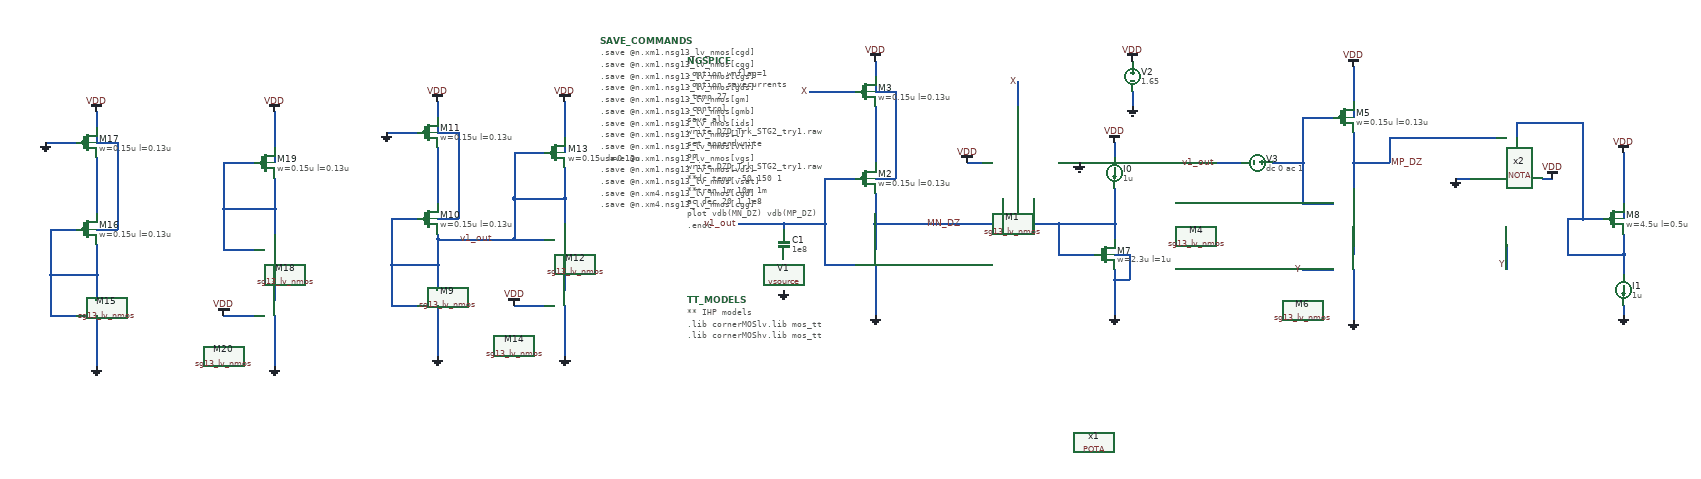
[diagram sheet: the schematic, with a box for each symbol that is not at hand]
v {xschem version=3.4.6 file_version=1.2}
G {}
K {}
V {}
S {}
E {}
N 370 -200 370 -100 {lab=GND}
N 270 -200 330 -200 {lab=v1_out}
N 270 -280 270 -200 {lab=v1_out}
N 270 -370 330 -370 {lab=v1_out}
N 370 -510 370 -400 {lab=#net1}
N 370 -370 410 -370 {lab=VDD}
N 410 -540 410 -370 {lab=VDD}
N 370 -600 370 -540 {lab=VDD}
N 370 -540 410 -540 {lab=VDD}
N 270 -370 270 -280 {lab=v1_out}
N 875 -540 875 -510 {lab=GND}
N 370 -280 370 -230 {lab=MN_DZ}
N 1310 -320 1310 -220 {lab=#net2}
N 1210 -320 1270 -320 {lab=#net3}
N 1210 -400 1210 -320 {lab=#net3}
N 1210 -490 1270 -490 {lab=#net3}
N 1150 -400 1210 -400 {lab=#net3}
N 1210 -490 1210 -400 {lab=#net3}
N 1310 -400 1310 -350 {lab=MP_DZ}
N 1310 -590 1310 -490 {lab=VDD}
N 1310 -190 1310 -90 {lab=GND}
N 1210 -190 1270 -190 {lab=Y}
N 840 -220 870 -220 {lab=GND}
N 870 -220 870 -170 {lab=GND}
N 840 -170 870 -170 {lab=GND}
N 840 -190 840 -170 {lab=GND}
N 730 -220 800 -220 {lab=#net4}
N 730 -280 730 -220 {lab=#net4}
N 730 -280 840 -280 {lab=#net4}
N 840 -280 840 -250 {lab=#net4}
N 840 -350 840 -280 {lab=#net4}
N 840 -170 840 -100 {lab=GND}
N 840 -440 840 -410 {lab=VDD}
N 550 -400 580 -400 {lab=VDD}
N 730 -400 770 -400 {lab=GND}
N 650 -560 650 -510 {lab=X}
N 240 -540 330 -540 {lab=X}
N 680 -280 730 -280 {lab=#net4}
N 1760 -290 1800 -290 {lab=#net5}
N 1730 -290 1730 -220 {lab=#net5}
N 1730 -220 1840 -220 {lab=#net5}
N 1840 -260 1840 -220 {lab=#net5}
N 1840 -420 1840 -290 {lab=VDD}
N 1840 -220 1840 -180 {lab=#net5}
N 1840 -120 1840 -100 {lab=GND}
N 1510 -370 1540 -370 {lab=GND}
N 1680 -370 1700 -370 {lab=VDD}
N 1630 -480 1630 -450 {lab=#net5}
N 1630 -480 1760 -480 {lab=#net5}
N 1760 -480 1760 -290 {lab=#net5}
N 1730 -290 1760 -290 {lab=#net5}
N 1610 -240 1610 -190 {lab=Y}
N 1310 -400 1380 -400 {lab=MP_DZ}
N 1310 -460 1310 -400 {lab=MP_DZ}
N 680 -330 680 -280 {lab=#net4}
N 620 -330 620 -280 {lab=MN_DZ}
N -490 -120 -490 -20 {lab=GND}
N -490 -430 -490 -320 {lab=#net6}
N -490 -290 -450 -290 {lab=VDD}
N -450 -460 -450 -290 {lab=VDD}
N -490 -520 -490 -460 {lab=VDD}
N -490 -460 -450 -460 {lab=VDD}
N -490 -200 -490 -150 {lab=v1_out}
N -580 -120 -530 -120 {lab=v1_out}
N -580 -200 -580 -120 {lab=v1_out}
N -580 -290 -530 -290 {lab=v1_out}
N -590 -460 -530 -460 {lab=GND}
N -580 -200 -490 -200 {lab=v1_out}
N -580 -290 -580 -200 {lab=v1_out}
N -490 -250 -490 -200 {lab=v1_out}
N -240 -250 -240 -150 {lab=#net7}
N -340 -250 -280 -250 {lab=v1_out}
N -340 -420 -280 -420 {lab=v1_out}
N -340 -330 -340 -250 {lab=v1_out}
N -240 -520 -240 -420 {lab=VDD}
N -240 -120 -240 -20 {lab=GND}
N -340 -120 -280 -120 {lab=VDD}
N -240 -330 -240 -280 {lab=v1_out}
N -340 -330 -240 -330 {lab=v1_out}
N -340 -420 -340 -330 {lab=v1_out}
N -240 -390 -240 -330 {lab=v1_out}
N -490 -250 -340 -250 {lab=v1_out}
N -490 -260 -490 -250 {lab=v1_out}
N 100 -280 190 -280 {lab=v1_out}
N 1040 -400 1090 -400 {lab=v1_out}
N 370 -280 620 -280 {lab=MN_DZ}
N 370 -340 370 -280 {lab=MN_DZ}
N 1380 -450 1380 -400 {lab=MP_DZ}
N 1380 -450 1590 -450 {lab=MP_DZ}
N -1160 -100 -1160 0 {lab=GND}
N -1160 -410 -1160 -300 {lab=#net8}
N -1160 -270 -1120 -270 {lab=VDD}
N -1120 -440 -1120 -270 {lab=VDD}
N -1160 -500 -1160 -440 {lab=VDD}
N -1160 -440 -1120 -440 {lab=VDD}
N -1160 -180 -1160 -130 {lab=#net9}
N -1250 -100 -1200 -100 {lab=#net9}
N -1250 -180 -1250 -100 {lab=#net9}
N -1250 -270 -1200 -270 {lab=#net9}
N -1260 -440 -1200 -440 {lab=GND}
N -1250 -180 -1160 -180 {lab=#net9}
N -1250 -270 -1250 -180 {lab=#net9}
N -1160 -240 -1160 -180 {lab=#net9}
N -810 -230 -810 -130 {lab=#net10}
N -910 -230 -850 -230 {lab=#net11}
N -910 -400 -850 -400 {lab=#net11}
N -910 -310 -910 -230 {lab=#net11}
N -810 -500 -810 -400 {lab=VDD}
N -810 -100 -810 0 {lab=GND}
N -910 -100 -850 -100 {lab=VDD}
N -810 -310 -810 -260 {lab=#net11}
N -910 -310 -810 -310 {lab=#net11}
N -910 -400 -910 -310 {lab=#net11}
N -810 -370 -810 -310 {lab=#net11}
N 190 -280 190 -270 {lab=v1_out}
N 190 -280 270 -280 {lab=v1_out}
C {/foss/designs/fd_pr/sg13_lv_nmos.sym} 270 -120 0 0 {name=M1
l=0.13u
w=0.15u
ng=1
m=1
model=sg13_lv_nmos
spiceprefix=X
}
C {/foss/designs/fd_pr/sg13_lv_pmos.sym} 350 -370 0 0 {name=M2
l=0.13u
w=0.15u
ng=1
m=3
model=sg13_lv_pmos
spiceprefix=X
}
C {vdd.sym} 370 -600 0 0 {name=l2 lab=VDD}
C {vsource.sym} 875 -570 0 0 {name=V2 value=1.65 savecurrent=false}
C {gnd.sym} 875 -510 0 0 {name=l3 lab=GND}
C {vdd.sym} 875 -600 0 0 {name=l4 lab=VDD}
C {gnd.sym} 370 -100 0 0 {name=l5 lab=GND}
C {/foss/designs/fd_pr/sg13_lv_nmos.sym} 1210 -240 0 0 {name=M4
l=0.13u
w=0.15u
ng=1
m=1
model=sg13_lv_nmos
spiceprefix=X
}
C {/foss/designs/fd_pr/sg13_lv_pmos.sym} 1290 -490 0 0 {name=M5
l=0.13u
w=0.15u
ng=1
m=1
model=sg13_lv_pmos
spiceprefix=X
}
C {vdd.sym} 1310 -590 0 0 {name=l7 lab=VDD}
C {/foss/designs/fd_pr/sg13_lv_nmos.sym} 1210 -110 0 0 {name=M6
l=0.13u
w=0.15u
ng=1
m=1
model=sg13_lv_nmos
spiceprefix=X
}
C {gnd.sym} 1310 -90 0 0 {name=l9 lab=GND}
C {/foss/designs/fd_pr/sg13_hv_nmos.sym} 820 -220 0 0 {name=M7
l=1u
w=2.3u
ng=1
m=1
model=sg13_hv_nmos
spiceprefix=X
}
C {isource.sym} 840 -380 0 0 {name=I0 value=1u}
C {vdd.sym} 840 -440 0 0 {name=l8 lab=VDD}
C {gnd.sym} 840 -100 0 0 {name=l10 lab=GND}
C {ngspice_probe.sym} 730 -280 0 0 {name=r1}
C {/foss/designs/RAMP/OTA/POTA.sym} 800 150 3 0 {name=x1}
C {vdd.sym} 550 -400 3 0 {name=l11 lab=VDD}
C {gnd.sym} 770 -400 0 0 {name=l12 lab=GND}
C {lab_pin.sym} 650 -560 1 0 {name=p1 sig_type=std_logic lab=X}
C {lab_pin.sym} 240 -540 0 0 {name=p2 sig_type=std_logic lab=X}
C {ngspice_probe.sym} 370 -280 0 0 {name=r2}
C {sg13g2_pr/sg13_hv_pmos.sym} 1820 -290 0 0 {name=M8
l=0.5u
w=4.5u
ng=1
m=1
model=sg13_hv_pmos
spiceprefix=X
}
C {isource.sym} 1840 -150 0 0 {name=I1 value=1u}
C {vdd.sym} 1840 -420 0 0 {name=l13 lab=VDD}
C {gnd.sym} 1840 -100 0 0 {name=l14 lab=GND}
C {ngspice_probe.sym} 1730 -250 0 0 {name=r3}
C {/foss/designs/RAMP/OTA/NOTA.sym} 1610 -650 3 1 {name=x2}
C {vdd.sym} 1700 -370 1 0 {name=l15 lab=VDD}
C {gnd.sym} 1510 -370 0 0 {name=l16 lab=GND}
C {lab_pin.sym} 1610 -200 3 0 {name=p3 sig_type=std_logic lab=Y}
C {lab_pin.sym} 1210 -190 0 0 {name=p4 sig_type=std_logic lab=Y}
C {ngspice_probe.sym} 1310 -400 0 1 {name=r4}
C {title.sym} 160 -30 0 0 {name=l17 author="Nithin Purushothama"}
C {devices/code_shown.sym} 0 -600 0 0 {name="NGSPICE" only_toplevel=true 
value="
.option wnflag=1
.option savecurrents
.temp 27
.control
save all
write DZD_Trk_STG2_try1.raw
set appendwrite 
op
write DZD_Trk_STG2_try1.raw
**dc temp -50 150 1
**tran 1m 10m 1m
ac dec 20 1 1e8
plot vdb(MN_DZ) vdb(MP_DZ)
.endc
"}
C {code_shown.sym} 0 -130 0 0 {
name=TT_MODELS
only_toplevel=true
value="
** IHP models
.lib cornerMOSlv.lib mos_tt
.lib cornerMOShv.lib mos_tt
"
spice_ignore=false
      }
C {devices/launcher.sym} 540 -130 0 0 {name=h1
descr="load op & annotate" 
tclcommand="xschem raw_read $netlist_dir/Deadzone_try_1.raw; set show_hidden_texts 1; xschem annotate_op"}
C {/foss/designs/fd_pr/sg13_lv_nmos.sym} -590 -40 0 0 {name=M9
l=0.13u
w=0.15u
ng=1
m=1
model=sg13_lv_nmos
spiceprefix=X
}
C {/foss/designs/fd_pr/sg13_lv_pmos.sym} -510 -290 0 0 {name=M10
l=0.13u
w=0.15u
ng=1
m=3
model=sg13_lv_pmos
spiceprefix=X
}
C {/foss/designs/fd_pr/sg13_lv_pmos.sym} -510 -460 0 0 {name=M11
l=0.13u
w=0.15u
ng=1
m=5
model=sg13_lv_pmos
spiceprefix=X
}
C {vdd.sym} -490 -520 0 0 {name=l18 lab=VDD}
C {gnd.sym} -490 -20 0 0 {name=l19 lab=GND}
C {ngspice_probe.sym} -490 -200 0 0 {name=r10}
C {gnd.sym} -590 -460 0 0 {name=l20 lab=GND}
C {/foss/designs/fd_pr/sg13_lv_nmos.sym} -340 -170 0 0 {name=M12
l=0.13u
w=0.15u
ng=1
m=1
model=sg13_lv_nmos
spiceprefix=X
}
C {/foss/designs/fd_pr/sg13_lv_pmos.sym} -260 -420 0 0 {name=M13
l=0.13u
w=0.15u
ng=1
m=1
model=sg13_lv_pmos
spiceprefix=X
}
C {vdd.sym} -240 -520 0 0 {name=l21 lab=VDD}
C {/foss/designs/fd_pr/sg13_lv_nmos.sym} -340 -40 0 0 {name=M14
l=0.13u
w=0.15u
ng=1
m=1
model=sg13_lv_nmos
spiceprefix=X
}
C {gnd.sym} -240 -20 0 0 {name=l22 lab=GND}
C {ngspice_probe.sym} -240 -330 0 0 {name=r11}
C {vdd.sym} -340 -120 0 0 {name=l23 lab=VDD}
C {lab_pin.sym} -380 -250 3 0 {name=p5 sig_type=std_logic lab=v1_out}
C {lab_pin.sym} 100 -280 0 0 {name=p6 sig_type=std_logic lab=v1_out}
C {lab_pin.sym} 1040 -400 0 0 {name=p7 sig_type=std_logic lab=v1_out}
C {vsource.sym} 190 -180 0 0 {name=V1 value="dc 0 ac 1" savecurrent=false}
C {vsource.sym} 1120 -400 1 0 {name=V3 value="dc 0 ac 1" savecurrent=false}
C {lab_pin.sym} 540 -280 3 0 {name=p8 sig_type=std_logic lab=MN_DZ}
C {lab_pin.sym} 1380 -400 2 0 {name=p9 sig_type=std_logic lab=MP_DZ}
C {ngspice_probe.sym} 270 -280 0 0 {name=r5}
C {ngspice_probe.sym} 1210 -400 0 0 {name=r6}
C {ngspice_probe.sym} 370 -440 0 0 {name=r7}
C {code.sym} -170 -640 0 0 {name=SAVE_COMMANDS only_toplevel=false value="
.save @n.xm1.nsg13_lv_nmos[cgd]
.save @n.xm1.nsg13_lv_nmos[cgg]
.save @n.xm1.nsg13_lv_nmos[cgs]
.save @n.xm1.nsg13_lv_nmos[gds]
.save @n.xm1.nsg13_lv_nmos[gm]
.save @n.xm1.nsg13_lv_nmos[gmb]
.save @n.xm1.nsg13_lv_nmos[ids]
.save @n.xm1.nsg13_lv_nmos[l]
.save @n.xm1.nsg13_lv_nmos[vth]
.save @n.xm1.nsg13_lv_nmos[vgs]
.save @n.xm1.nsg13_lv_nmos[vds]
.save @n.xm1.nsg13_lv_nmos[vsat]
.save @n.xm4.nsg13_lv_nmos[cgd]
.save @n.xm4.nsg13_lv_nmos[cgg]
.save @n.xm4.nsg13_lv_nmos[cgs]
.save @n.xm4.nsg13_lv_nmos[gds]
.save @n.xm4.nsg13_lv_nmos[gm]
.save @n.xm4.nsg13_lv_nmos[gmb]
.save @n.xm4.nsg13_lv_nmos[ids]
.save @n.xm4.nsg13_lv_nmos[l]
.save @n.xm4.nsg13_lv_nmos[vth]
.save @n.xm4.nsg13_lv_nmos[vgs]
.save @n.xm4.nsg13_lv_nmos[vds]
.save @n.xm4.nsg13_lv_nmos[vsat]
.save @n.xm6.nsg13_lv_nmos[cgd]
.save @n.xm6.nsg13_lv_nmos[cgg]
.save @n.xm6.nsg13_lv_nmos[cgs]
.save @n.xm6.nsg13_lv_nmos[gds]
.save @n.xm6.nsg13_lv_nmos[gm]
.save @n.xm6.nsg13_lv_nmos[gmb]
.save @n.xm6.nsg13_lv_nmos[ids]
.save @n.xm6.nsg13_lv_nmos[l]
.save @n.xm6.nsg13_lv_nmos[vth]
.save @n.xm6.nsg13_lv_nmos[vgs]
.save @n.xm6.nsg13_lv_nmos[vds]
.save @n.xm6.nsg13_lv_nmos[vsat]
.save @n.xm9.nsg13_lv_nmos[cgd]
.save @n.xm9.nsg13_lv_nmos[cgg]
.save @n.xm9.nsg13_lv_nmos[cgs]
.save @n.xm9.nsg13_lv_nmos[gds]
.save @n.xm9.nsg13_lv_nmos[gm]
.save @n.xm9.nsg13_lv_nmos[gmb]
.save @n.xm9.nsg13_lv_nmos[ids]
.save @n.xm9.nsg13_lv_nmos[l]
.save @n.xm9.nsg13_lv_nmos[vth]
.save @n.xm9.nsg13_lv_nmos[vgs]
.save @n.xm9.nsg13_lv_nmos[vds]
.save @n.xm9.nsg13_lv_nmos[vsat]
.save @n.xm12.nsg13_lv_nmos[cgd]
.save @n.xm12.nsg13_lv_nmos[cgg]
.save @n.xm12.nsg13_lv_nmos[cgs]
.save @n.xm12.nsg13_lv_nmos[gds]
.save @n.xm12.nsg13_lv_nmos[gm]
.save @n.xm12.nsg13_lv_nmos[gmb]
.save @n.xm12.nsg13_lv_nmos[ids]
.save @n.xm12.nsg13_lv_nmos[l]
.save @n.xm12.nsg13_lv_nmos[vth]
.save @n.xm12.nsg13_lv_nmos[vgs]
.save @n.xm12.nsg13_lv_nmos[vds]
.save @n.xm12.nsg13_lv_nmos[vsat]
.save @n.xm14.nsg13_lv_nmos[cgd]
.save @n.xm14.nsg13_lv_nmos[cgg]
.save @n.xm14.nsg13_lv_nmos[cgs]
.save @n.xm14.nsg13_lv_nmos[gds]
.save @n.xm14.nsg13_lv_nmos[gm]
.save @n.xm14.nsg13_lv_nmos[gmb]
.save @n.xm14.nsg13_lv_nmos[ids]
.save @n.xm14.nsg13_lv_nmos[l]
.save @n.xm14.nsg13_lv_nmos[vth]
.save @n.xm14.nsg13_lv_nmos[vgs]
.save @n.xm14.nsg13_lv_nmos[vds]
.save @n.xm14.nsg13_lv_nmos[vsat]
.save @n.xm15.nsg13_lv_nmos[cgd]
.save @n.xm15.nsg13_lv_nmos[cgg]
.save @n.xm15.nsg13_lv_nmos[cgs]
.save @n.xm15.nsg13_lv_nmos[gds]
.save @n.xm15.nsg13_lv_nmos[gm]
.save @n.xm15.nsg13_lv_nmos[gmb]
.save @n.xm15.nsg13_lv_nmos[ids]
.save @n.xm15.nsg13_lv_nmos[l]
.save @n.xm15.nsg13_lv_nmos[vth]
.save @n.xm15.nsg13_lv_nmos[vgs]
.save @n.xm15.nsg13_lv_nmos[vds]
.save @n.xm15.nsg13_lv_nmos[vsat]
.save @n.xm18.nsg13_lv_nmos[cgd]
.save @n.xm18.nsg13_lv_nmos[cgg]
.save @n.xm18.nsg13_lv_nmos[cgs]
.save @n.xm18.nsg13_lv_nmos[gds]
.save @n.xm18.nsg13_lv_nmos[gm]
.save @n.xm18.nsg13_lv_nmos[gmb]
.save @n.xm18.nsg13_lv_nmos[ids]
.save @n.xm18.nsg13_lv_nmos[l]
.save @n.xm18.nsg13_lv_nmos[vth]
.save @n.xm18.nsg13_lv_nmos[vgs]
.save @n.xm18.nsg13_lv_nmos[vds]
.save @n.xm18.nsg13_lv_nmos[vsat]
.save @n.xm20.nsg13_lv_nmos[cgd]
.save @n.xm20.nsg13_lv_nmos[cgg]
.save @n.xm20.nsg13_lv_nmos[cgs]
.save @n.xm20.nsg13_lv_nmos[gds]
.save @n.xm20.nsg13_lv_nmos[gm]
.save @n.xm20.nsg13_lv_nmos[gmb]
.save @n.xm20.nsg13_lv_nmos[ids]
.save @n.xm20.nsg13_lv_nmos[l]
.save @n.xm20.nsg13_lv_nmos[vth]
.save @n.xm20.nsg13_lv_nmos[vgs]
.save @n.xm20.nsg13_lv_nmos[vds]
.save @n.xm20.nsg13_lv_nmos[vsat]
.save @n.xm2.nsg13_lv_pmos[cgd]
.save @n.xm2.nsg13_lv_pmos[cgg]
.save @n.xm2.nsg13_lv_pmos[cgs]
.save @n.xm2.nsg13_lv_pmos[gds]
.save @n.xm2.nsg13_lv_pmos[gm]
.save @n.xm2.nsg13_lv_pmos[gmb]
.save @n.xm2.nsg13_lv_pmos[ids]
.save @n.xm2.nsg13_lv_pmos[l]
.save @n.xm2.nsg13_lv_pmos[vth]
.save @n.xm2.nsg13_lv_pmos[vgs]
.save @n.xm2.nsg13_lv_pmos[vds]
.save @n.xm2.nsg13_lv_pmos[vsat]
.save @n.xm3.nsg13_lv_pmos[cgd]
.save @n.xm3.nsg13_lv_pmos[cgg]
.save @n.xm3.nsg13_lv_pmos[cgs]
.save @n.xm3.nsg13_lv_pmos[gds]
.save @n.xm3.nsg13_lv_pmos[gm]
.save @n.xm3.nsg13_lv_pmos[gmb]
.save @n.xm3.nsg13_lv_pmos[ids]
.save @n.xm3.nsg13_lv_pmos[l]
.save @n.xm3.nsg13_lv_pmos[vth]
.save @n.xm3.nsg13_lv_pmos[vgs]
.save @n.xm3.nsg13_lv_pmos[vds]
.save @n.xm3.nsg13_lv_pmos[vsat]
.save @n.xm5.nsg13_lv_pmos[cgd]
.save @n.xm5.nsg13_lv_pmos[cgg]
.save @n.xm5.nsg13_lv_pmos[cgs]
.save @n.xm5.nsg13_lv_pmos[gds]
.save @n.xm5.nsg13_lv_pmos[gm]
.save @n.xm5.nsg13_lv_pmos[gmb]
.save @n.xm5.nsg13_lv_pmos[ids]
.save @n.xm5.nsg13_lv_pmos[l]
.save @n.xm5.nsg13_lv_pmos[vth]
.save @n.xm5.nsg13_lv_pmos[vgs]
.save @n.xm5.nsg13_lv_pmos[vds]
.save @n.xm5.nsg13_lv_pmos[vsat]
.save @n.xm10.nsg13_lv_pmos[cgd]
.save @n.xm10.nsg13_lv_pmos[cgg]
.save @n.xm10.nsg13_lv_pmos[cgs]
.save @n.xm10.nsg13_lv_pmos[gds]
.save @n.xm10.nsg13_lv_pmos[gm]
.save @n.xm10.nsg13_lv_pmos[gmb]
.save @n.xm10.nsg13_lv_pmos[ids]
.save @n.xm10.nsg13_lv_pmos[l]
.save @n.xm10.nsg13_lv_pmos[vth]
.save @n.xm10.nsg13_lv_pmos[vgs]
.save @n.xm10.nsg13_lv_pmos[vds]
.save @n.xm10.nsg13_lv_pmos[vsat]
.save @n.xm11.nsg13_lv_pmos[cgd]
.save @n.xm11.nsg13_lv_pmos[cgg]
.save @n.xm11.nsg13_lv_pmos[cgs]
.save @n.xm11.nsg13_lv_pmos[gds]
.save @n.xm11.nsg13_lv_pmos[gm]
.save @n.xm11.nsg13_lv_pmos[gmb]
.save @n.xm11.nsg13_lv_pmos[ids]
.save @n.xm11.nsg13_lv_pmos[l]
.save @n.xm11.nsg13_lv_pmos[vth]
.save @n.xm11.nsg13_lv_pmos[vgs]
.save @n.xm11.nsg13_lv_pmos[vds]
.save @n.xm11.nsg13_lv_pmos[vsat]
.save @n.xm13.nsg13_lv_pmos[cgd]
.save @n.xm13.nsg13_lv_pmos[cgg]
.save @n.xm13.nsg13_lv_pmos[cgs]
.save @n.xm13.nsg13_lv_pmos[gds]
.save @n.xm13.nsg13_lv_pmos[gm]
.save @n.xm13.nsg13_lv_pmos[gmb]
.save @n.xm13.nsg13_lv_pmos[ids]
.save @n.xm13.nsg13_lv_pmos[l]
.save @n.xm13.nsg13_lv_pmos[vth]
.save @n.xm13.nsg13_lv_pmos[vgs]
.save @n.xm13.nsg13_lv_pmos[vds]
.save @n.xm13.nsg13_lv_pmos[vsat]
.save @n.xm16.nsg13_lv_pmos[cgd]
.save @n.xm16.nsg13_lv_pmos[cgg]
.save @n.xm16.nsg13_lv_pmos[cgs]
.save @n.xm16.nsg13_lv_pmos[gds]
.save @n.xm16.nsg13_lv_pmos[gm]
.save @n.xm16.nsg13_lv_pmos[gmb]
.save @n.xm16.nsg13_lv_pmos[ids]
.save @n.xm16.nsg13_lv_pmos[l]
.save @n.xm16.nsg13_lv_pmos[vth]
.save @n.xm16.nsg13_lv_pmos[vgs]
.save @n.xm16.nsg13_lv_pmos[vds]
.save @n.xm16.nsg13_lv_pmos[vsat]
.save @n.xm17.nsg13_lv_pmos[cgd]
.save @n.xm17.nsg13_lv_pmos[cgg]
.save @n.xm17.nsg13_lv_pmos[cgs]
.save @n.xm17.nsg13_lv_pmos[gds]
.save @n.xm17.nsg13_lv_pmos[gm]
.save @n.xm17.nsg13_lv_pmos[gmb]
.save @n.xm17.nsg13_lv_pmos[ids]
.save @n.xm17.nsg13_lv_pmos[l]
.save @n.xm17.nsg13_lv_pmos[vth]
.save @n.xm17.nsg13_lv_pmos[vgs]
.save @n.xm17.nsg13_lv_pmos[vds]
.save @n.xm17.nsg13_lv_pmos[vsat]
.save @n.xm19.nsg13_lv_pmos[cgd]
.save @n.xm19.nsg13_lv_pmos[cgg]
.save @n.xm19.nsg13_lv_pmos[cgs]
.save @n.xm19.nsg13_lv_pmos[gds]
.save @n.xm19.nsg13_lv_pmos[gm]
.save @n.xm19.nsg13_lv_pmos[gmb]
.save @n.xm19.nsg13_lv_pmos[ids]
.save @n.xm19.nsg13_lv_pmos[l]
.save @n.xm19.nsg13_lv_pmos[vth]
.save @n.xm19.nsg13_lv_pmos[vgs]
.save @n.xm19.nsg13_lv_pmos[vds]
.save @n.xm19.nsg13_lv_pmos[vsat]
"}
C {/foss/designs/fd_pr/sg13_lv_pmos.sym} 350 -540 0 0 {name=M3
l=0.13u
w=0.15u
ng=1
m=5
model=sg13_lv_pmos
spiceprefix=X
}
C {/foss/designs/fd_pr/sg13_lv_nmos.sym} -1260 -20 0 0 {name=M15
l=0.13u
w=0.15u
ng=1
m=1
model=sg13_lv_nmos
spiceprefix=X
}
C {/foss/designs/fd_pr/sg13_lv_pmos.sym} -1180 -270 0 0 {name=M16
l=0.13u
w=0.15u
ng=1
m=3
model=sg13_lv_pmos
spiceprefix=X
}
C {/foss/designs/fd_pr/sg13_lv_pmos.sym} -1180 -440 0 0 {name=M17
l=0.13u
w=0.15u
ng=1
m=5
model=sg13_lv_pmos
spiceprefix=X
}
C {vdd.sym} -1160 -500 0 0 {name=l1 lab=VDD}
C {gnd.sym} -1160 0 0 0 {name=l6 lab=GND}
C {ngspice_probe.sym} -1160 -180 0 0 {name=r8}
C {gnd.sym} -1260 -440 0 0 {name=l24 lab=GND}
C {/foss/designs/fd_pr/sg13_lv_nmos.sym} -910 -150 0 0 {name=M18
l=0.13u
w=0.15u
ng=1
m=1
model=sg13_lv_nmos
spiceprefix=X
}
C {/foss/designs/fd_pr/sg13_lv_pmos.sym} -830 -400 0 0 {name=M19
l=0.13u
w=0.15u
ng=1
m=1
model=sg13_lv_pmos
spiceprefix=X
}
C {vdd.sym} -810 -500 0 0 {name=l25 lab=VDD}
C {/foss/designs/fd_pr/sg13_lv_nmos.sym} -910 -20 0 0 {name=M20
l=0.13u
w=0.15u
ng=1
m=1
model=sg13_lv_nmos
spiceprefix=X
}
C {gnd.sym} -810 0 0 0 {name=l26 lab=GND}
C {ngspice_probe.sym} -810 -310 0 0 {name=r9}
C {vdd.sym} -910 -100 0 0 {name=l27 lab=VDD}
C {capa.sym} 190 -240 0 0 {name=C1
m=1
value=1e8
footprint=1206
device="ceramic capacitor"}
C {gnd.sym} 190 -150 0 0 {name=l28 lab=GND}
